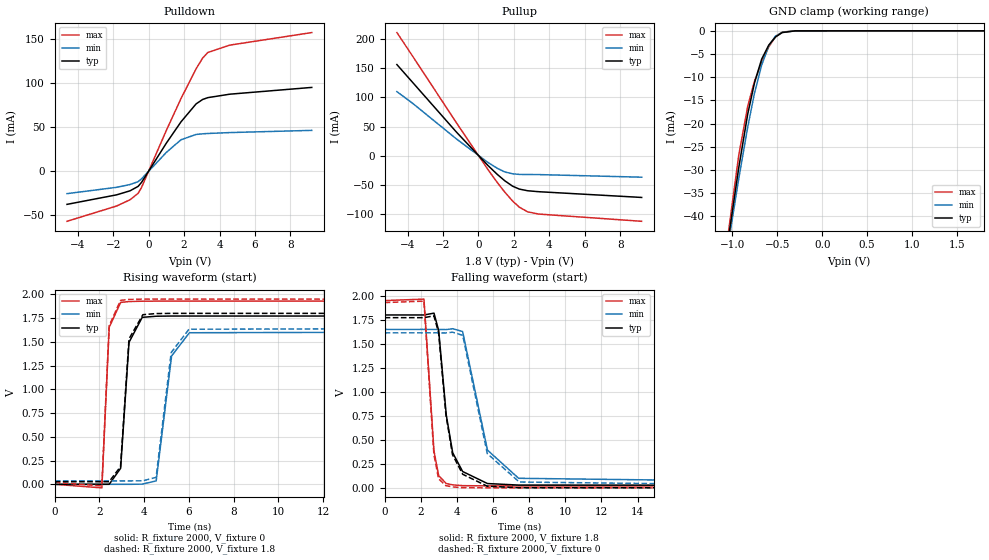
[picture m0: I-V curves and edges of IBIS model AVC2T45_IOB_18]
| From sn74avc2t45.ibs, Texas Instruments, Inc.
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[Model]   AVC2T45_IOB_18
Model_type  I/O
Vinl=0.5775
Vinh=1.2675
Enable   Active-High
Vref =   0
Rref =   2000
Cref =   15p
Vmeas =   0.9
| variable   typ   min   max
C_comp   5.13pF   4.43pF   5.79pF
| C_pullup   4.65pF   3.47pF   6.78pF
| C_pulldown   4.55pF   4.02pF   4.94pF
| C_tri-state   5.13pF   4.43pF   5.79pF
[Temperature Range]   40   100   -40
| Ambient temperature   25   85   -40
[Voltage range]   1.8   1.65   1.95
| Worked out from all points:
|   slope of the pulldown table from 0 to 0.27 V, typ, clamps not added: 30.8 ohm
|   slope of the pullup table from 0 to 0.27 V, typ, clamps not added: 31.4 ohm
|   GND clamp passes 1 mA (typ) near -0.50 V on its own axis
|   rising waveform, R_fixture 2000, V_fixture 0: 20-80 % time 283ps typ, 440ps min, 181ps max; typ from 0 V to 1.77 V
|   falling waveform, R_fixture 2000, V_fixture 1.8: 20-80 % time 647ps typ, 989ps min, 373ps max; typ from 1.8 V to 0.027 V
|   rising waveform, R_fixture 2000, V_fixture 1.8: 20-80 % time 281ps typ, 432ps min, 180ps max; typ from 0.027 V to 1.8 V
|   falling waveform, R_fixture 2000, V_fixture 0: 20-80 % time 649ps typ, 989ps min, 360ps max; typ from 1.77 V to 0 V
[GND Clamp]
| AVC2T45_IOB_18
|   Voltage   I(typ)   I(min)   I(max)
-4.6V     -597.8mA   -546.6mA   -662.5mA
-1.1V     -52.11mA   -52.52mA   -51.59mA
-1.075V   -48.66mA   -49.4mA    -47.7mA
-930mV    -29.5mA    -31.88mA   -26.82mA
-830mV    -17.94mA   -20.74mA   -16.24mA
-755mV    -11.24mA   -13.46mA   -10.89mA
-675mV    -6.119mA   -7.407mA   -6.788mA
-595mV    -3.054mA   -3.247mA   -3.436mA
-520mV    -1.318mA   -1.132mA   -1.268mA
-445mV    -373.4uA   -312uA     -266.4uA
-300mV    -9.535uA   -12.09uA   -2.471uA
1.8V      910.1pA    145.3nA    97.77pA
[Pulldown]
| AVC2T45_IOB_18
|   Voltage   I(typ)   I(min)   I(max)
-4.6V     -37.94mA   -25.73mA   -57.23mA
-1.805V   -27.11mA   -18.54mA   -39.83mA
-1.045V   -22.5mA    -15.36mA   -32.7mA
-590mV    -17.44mA   -12.06mA   -25.35mA
-395mV    -12.81mA   -8.801mA   -18.52mA
1.005V    31.93mA    21.31mA    46.48mA
1.825V    55.97mA    35.61mA    82.46mA
2.68V     76.51mA    41.68mA    116.5mA
3.045V    81.48mA    42.38mA    128.6mA
3.34V     83.6mA     42.77mA    135mA
4.58V     87.53mA    43.81mA    143.4mA
9.2V      95.24mA    46.32mA    157.7mA
[Pullup]
| AVC2T45_IOB_18
|   Voltage   I(typ)   I(min)   I(max)
-4.6V     156.3mA    109.9mA    211.2mA
-3.695V   125.1mA    89.45mA    169.9mA
-1.245V   40.55mA    28.8mA     56.51mA
535mV     -16.77mA   -11.6mA    -23.84mA
1.065V    -32.16mA   -21.66mA   -46.14mA
1.49V     -43.16mA   -27.88mA   -62.67mA
1.925V    -52.28mA   -31.05mA   -77.72mA
2.305V    -57.27mA   -32.09mA   -88.3mA
2.77V     -60.1mA    -32.26mA   -96.25mA
3.4V      -61.74mA   -32.39mA   -100.1mA
9.2V      -71.58mA   -36.85mA   -112.5mA
[Ramp]
| AVC2T45_IOB_18
| variable   typ   min   max
dV/dt_r   1.08/3.00E-10   0.99/4.54E-10   1.18/1.87E-10
dV/dt_f   1.08/6.52E-10   0.98/9.96E-10   1.17/3.77E-10
R_load = 2000
[Rising Waveform]
| AVC2T45_IOB_18
R_fixture =   2000
C_fixture =   0
L_fixture =   0
V_fixture =   0
V_fixture_min = 0
V_fixture_max = 0
|   Time   V(typ)   V(min)   V(max)
0s        21.36nV    98.35nV    643.7pV
2.105ns   38.9uV     6.392nV    -37.29mV
2.435ns   700.4uV    -19.6uV    1.654V
2.945ns   168.9mV    12.07uV    1.915V
3.32ns    1.495V     -166uV     1.925V
3.91ns    1.758V     2.006mV    1.928V
4.535ns   1.77V      36.1mV     1.929V
5.225ns   1.772V     1.352V     1.929V
6.02ns    1.772V     1.596V     1.929V
34.99ns   1.772V     1.614V     1.929V
[Falling Waveform]
| AVC2T45_IOB_18
R_fixture =   2000
C_fixture =   0
L_fixture =   0
V_fixture =   1.8
V_fixture_min = 1.65
V_fixture_max = 1.95
|   Time   V(typ)   V(min)   V(max)
0s        1.8V       1.65V      1.95V
2.175ns   1.8V       1.65V      1.965V
2.73ns    1.819V     1.65V      383.1mV
2.99ns    1.638V     1.649V     127mV
3.41ns    758.3mV    1.648V     44.91mV
3.765ns   365.9mV    1.657V     31.36mV
4.315ns   170.2mV    1.628V     23.04mV
5.69ns    44.91mV    393.1mV    20.55mV
7.415ns   29.02mV    99.5mV     20.46mV
34.99ns   27.15mV    36.2mV     20.45mV
[Rising Waveform]
| AVC2T45_IOB_18
R_fixture =   2000
C_fixture =   0
L_fixture =   0
V_fixture =   1.8
V_fixture_min = 1.65
V_fixture_max = 1.95
|   Time   V(typ)   V(min)   V(max)
0s        27.15mV    36.2mV     20.45mV
2.105ns   27.19mV    36.2mV     -16.69mV
2.43ns    27.76mV    36.19mV    1.669V
2.94ns    186.3mV    36.22mV    1.937V
3.32ns    1.532V     36.04mV    1.947V
3.94ns    1.786V     37.08mV    1.95V
4.53ns    1.798V     73.23mV    1.95V
5.205ns   1.8V       1.387V     1.95V
6ns       1.8V       1.633V     1.95V
34.99ns   1.8V       1.65V      1.95V
[Falling Waveform]
| AVC2T45_IOB_18
R_fixture =   2000
C_fixture =   0
L_fixture =   0
V_fixture =   0
V_fixture_min = 0
V_fixture_max = 0
|   Time   V(typ)   V(min)   V(max)
0s        1.772V     1.614V     1.929V
2.175ns   1.772V     1.614V     1.944V
2.725ns   1.791V     1.615V     347.9mV
2.985ns   1.616V     1.614V     93.85mV
3.39ns    762.5mV    1.613V     23.36mV
3.755ns   345.7mV    1.621V     9.755mV
4.32ns    141.6mV    1.588V     2.155mV
5.68ns    17.04mV    356.6mV    83.83uV
7.45ns    1.541mV    60.71mV    9.3uV
34.99ns   88.35nV    462.3nV    161.6nV
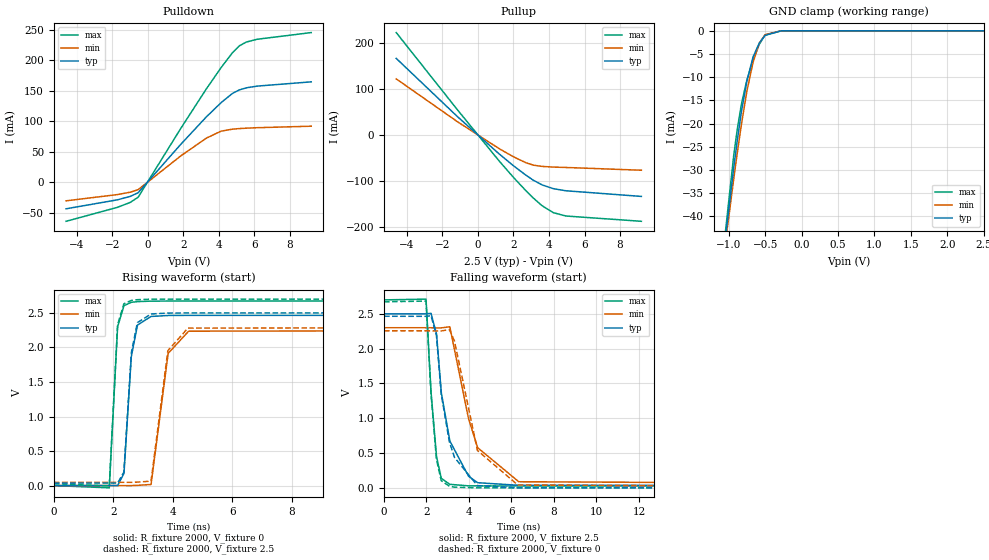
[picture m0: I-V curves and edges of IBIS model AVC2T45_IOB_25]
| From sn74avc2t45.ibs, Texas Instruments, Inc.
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[Model]   AVC2T45_IOB_25
Model_type  I/O
Vinl=0.7
Vinh=1.6
Enable   Active-High
Vref =   0
Rref =   2000
Cref =   15p
Vmeas =   1.25
| variable   typ   min   max
C_comp   4.92pF   4.20pF   5.67pF
| C_pullup   4.12pF   3.15pF   5.54pF
| C_pulldown   4.24pF   3.76pF   4.71pF
| C_tri-state   4.92pF   4.20pF   5.67pF
[Temperature Range]   40   100   -40
| Ambient temperature   25   85   -40
[Voltage range]   2.5   2.3   2.7
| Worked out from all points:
|   slope of the pulldown table from 0 to 0.375 V, typ, clamps not added: 29.4 ohm
|   slope of the pullup table from 0 to 0.375 V, typ, clamps not added: 28.8 ohm
|   GND clamp passes 1 mA (typ) near -0.50 V on its own axis
|   rising waveform, R_fixture 2000, V_fixture 0: 20-80 % time 218ps typ, 341ps min, 154ps max; typ from 0 V to 2.46 V
|   falling waveform, R_fixture 2000, V_fixture 2.5: 20-80 % time 730ps typ, 1.04ns min, 339ps max; typ from 2.5 V to 0.036 V
|   rising waveform, R_fixture 2000, V_fixture 2.5: 20-80 % time 217ps typ, 337ps min, 153ps max; typ from 0.036 V to 2.5 V
|   falling waveform, R_fixture 2000, V_fixture 0: 20-80 % time 722ps typ, 1.04ns min, 331ps max; typ from 2.46 V to 0 V
[GND Clamp]
| AVC2T45_IOB_25
|   Voltage   I(typ)   I(min)   I(max)
-4.6V     -597.8mA   -546.6mA   -662.5mA
-1.105V   -52.8mA    -53.15mA   -52.37mA
-1.08V    -49.35mA   -50.03mA   -48.48mA
-930mV    -29.5mA    -31.88mA   -26.82mA
-880mV    -23.45mA   -26.17mA   -21.02mA
-825mV    -17.44mA   -20.22mA   -15.81mA
-750mV    -10.86mA   -13.03mA   -10.61mA
-665mV    -5.629mA   -6.786mA   -6.326mA
-580mV    -2.642mA   -2.683mA   -2.914mA
-500mV    -988.4uA   -823.5uA   -890.7uA
-280mV    -5.263uA   -7.282uA   -1.131uA
2.5V      1.201nA    548.8nA    148.6pA
[Pulldown]
| AVC2T45_IOB_25
|   Voltage   I(typ)   I(min)   I(max)
-4.6V     -43.76mA   -30.71mA   -64.27mA
-1.71V    -29.04mA   -20.44mA   -41.4mA
-985mV    -23.44mA   -16.53mA   -33.24mA
-545mV    -17.41mA   -12.35mA   -24.86mA
1.85V     61.76mA    42.85mA    87.78mA
3.295V    106.9mA    72.08mA    152.8mA
4.12V     130.1mA    83.49mA    187.5mA
4.755V    145.2mA    86.77mA    211.8mA
5.15V     151.2mA    87.75mA    223.4mA
5.55V     154.6mA    88.43mA    229.7mA
6.155V    157.4mA    89.2mA     234.2mA
9.2V      164.4mA    91.67mA    245.2mA
[Pullup]
| AVC2T45_IOB_25
|   Voltage   I(typ)   I(min)   I(max)
-4.6V     167.2mA    122.6mA    223.3mA
-1.155V   40.55mA    29.45mA    55.44mA
1.195V    -40.71mA   -29.18mA   -56.05mA
2.025V    -67.14mA   -47.36mA   -92.77mA
2.69V     -86.59mA   -59.63mA   -120.2mA
3.115V    -97.78mA   -65.03mA   -136.5mA
3.61V     -108mA     -67.79mA   -153.3mA
4.245V    -116.2mA   -69.29mA   -168.4mA
4.95V     -120.8mA   -70.1mA    -175.7mA
9.2V      -133.1mA   -76.13mA   -187.2mA
[Ramp]
| AVC2T45_IOB_25
| variable   typ   min   max
dV/dt_r   1.49/2.26E-10   1.38/3.53E-10   1.63/1.60E-10
dV/dt_f   1.49/7.30E-10   1.36/1.04E-09   1.61/3.41E-10
R_load = 2000
[Rising Waveform]
| AVC2T45_IOB_25
R_fixture =   2000
C_fixture =   0
L_fixture =   0
V_fixture =   0
V_fixture_min = 0
V_fixture_max = 0
|   Time   V(typ)   V(min)   V(max)
0s        27.74nV    106.5nV    1.06nV
1.865ns   32.51uV    -2.132uV   -33.31mV
2.145ns   165.4uV    -29.52uV   2.299V
2.36ns    176.4mV    35.27uV    2.605V
2.605ns   1.866V     -218.6uV   2.654V
2.815ns   2.325V     3.095mV    2.664V
3.27ns    2.449V     15.8mV     2.671V
3.845ns   2.463V     1.914V     2.672V
4.535ns   2.465V     2.236V     2.672V
34.99ns   2.465V     2.256V     2.672V
[Falling Waveform]
| AVC2T45_IOB_25
R_fixture =   2000
C_fixture =   0
L_fixture =   0
V_fixture =   2.5
V_fixture_min = 2.3
V_fixture_max = 2.7
|   Time   V(typ)   V(min)   V(max)
0s        2.5V       2.3V       2.7V
1.98ns    2.499V     2.3V       2.711V
2.215ns   2.507V     2.3V       1.379V
2.475ns   2.208V     2.298V     446.3mV
2.7ns     1.365V     2.298V     136.1mV
3.1ns     673.8mV    2.314V     50.62mV
3.98ns    166.9mV    994.7mV    29.02mV
4.41ns    73.94mV    576.5mV    28.03mV
6.345ns   36.64mV    87.91mV    27.63mV
34.99ns   36.05mV    46.86mV    27.62mV
[Rising Waveform]
| AVC2T45_IOB_25
R_fixture =   2000
C_fixture =   0
L_fixture =   0
V_fixture =   2.5
V_fixture_min = 2.3
V_fixture_max = 2.7
|   Time   V(typ)   V(min)   V(max)
0s        36.05mV    46.86mV    27.62mV
1.865ns   36.09mV    46.85mV    -5.701mV
2.145ns   36.2mV     46.83mV    2.331V
2.355ns   193.7mV    46.89mV    2.632V
2.61ns    1.933V     46.65mV    2.682V
2.81ns    2.36V      49.84mV    2.692V
3.27ns    2.485V     64.05mV    2.699V
3.835ns   2.498V     1.954V     2.7V
4.51ns    2.5V       2.28V      2.7V
34.99ns   2.5V       2.3V       2.7V
[Falling Waveform]
| AVC2T45_IOB_25
R_fixture =   2000
C_fixture =   0
L_fixture =   0
V_fixture =   0
V_fixture_min = 0
V_fixture_max = 0
|   Time   V(typ)   V(min)   V(max)
0s        2.465V     2.256V     2.672V
1.98ns    2.464V     2.256V     2.683V
2.215ns   2.472V     2.256V     1.351V
2.47ns    2.189V     2.254V     407mV
2.695ns   1.347V     2.254V     103.7mV
3.08ns    659.5mV    2.273V     22.93mV
3.32ns    437mV      2.107V     10.44mV
4.4ns     31.98mV    537mV      385.4uV
6.3ns     508.2uV    40.75mV    13.68uV
34.99ns   384.9nV    342nV      234.7nV
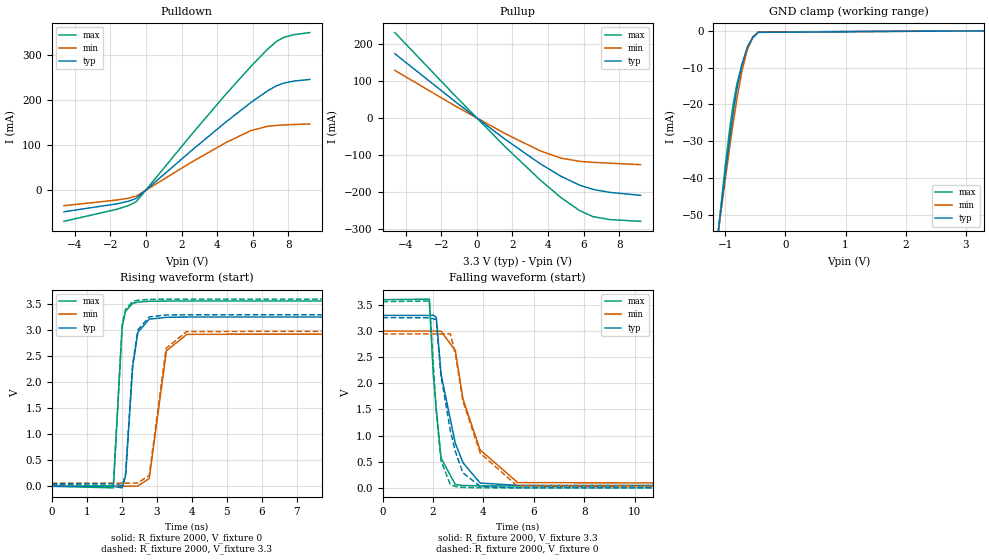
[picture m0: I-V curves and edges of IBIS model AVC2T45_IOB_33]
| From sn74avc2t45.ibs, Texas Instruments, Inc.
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[Model]   AVC2T45_IOB_33
Model_type  I/O
Vinl=0.8
Vinh=2.0
Enable   Active-High
Vref =   0
Rref =   2000
Cref =   15p
Vmeas =   1.65
| variable   typ   min   max
C_comp   4.80pF   3.94pF   5.78pF
| C_pullup   3.85pF   2.95pF   5.15pF
| C_pulldown   4.06pF   3.58pF   4.64pF
| C_tri-state   4.80pF   3.94pF   5.78pF
[Temperature Range]   40   100   -40
| Ambient temperature   25   85   -40
[Voltage range]   3.3   3   3.6
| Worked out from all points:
|   slope of the pulldown table from 0 to 0.495 V, typ, clamps not added: 28.7 ohm
|   slope of the pullup table from 0 to 0.495 V, typ, clamps not added: 27.4 ohm
|   GND clamp passes 1 mA (typ) near -0.50 V on its own axis
|   rising waveform, R_fixture 2000, V_fixture 0: 20-80 % time 197ps typ, 301ps min, 140ps max; typ from 0 V to 3.26 V
|   falling waveform, R_fixture 2000, V_fixture 3.3: 20-80 % time 746ps typ, 1ns min, 327ps max; typ from 3.3 V to 0.046 V
|   rising waveform, R_fixture 2000, V_fixture 3.3: 20-80 % time 196ps typ, 297ps min, 139ps max; typ from 0.046 V to 3.3 V
|   falling waveform, R_fixture 2000, V_fixture 0: 20-80 % time 663ps typ, 1ns min, 323ps max; typ from 3.26 V to 0 V
[GND Clamp]
| AVC2T45_IOB_33
|   Voltage   I(typ)   I(min)   I(max)
-4.6V     -597.8mA   -546.6mA   -662.5mA
-1.12V    -54.88mA   -55.04mA   -54.73mA
-1.09V    -50.72mA   -51.27mA   -50.03mA
-1V       -38.53mA   -40.19mA   -36.43mA
-920mV    -28.25mA   -30.71mA   -25.57mA
-870mV    -22.29mA   -25.06mA   -19.99mA
-810mV    -15.96mA   -18.69mA   -14.59mA
-725mV    -9.083mA   -10.96mA   -9.257mA
-630mV    -4.179mA   -4.838mA   -4.797mA
-545mV    -1.809mA   -1.649mA   -1.862mA
-450mV    -412.7uA   -343uA     -301.7uA
3.3V      1.631nA    2.406uA    228.2pA
[Pulldown]
| AVC2T45_IOB_33
|   Voltage   I(typ)   I(min)   I(max)
-4.6V     -47.48mA   -33.99mA   -68.59mA
-1.68V    -30.25mA   -21.7mA    -42.42mA
-975mV    -24.15mA   -17.32mA   -33.81mA
-545mV    -17.86mA   -12.84mA   -25.24mA
2.54V     87.35mA    61.85mA    122.6mA
4.5V      151.6mA    105.9mA    213.3mA
5.905V    194.7mA    132.4mA    274.8mA
6.805V    219.6mA    141.6mA    311.5mA
7.315V    231.2mA    143.7mA    329.3mA
7.73V     237.3mA    144.7mA    338.5mA
8.275V    241.7mA    145.7mA    344.4mA
9.2V      245.6mA    146.9mA    349.3mA
[Pullup]
| AVC2T45_IOB_33
|   Voltage   I(typ)   I(min)   I(max)
-4.6V     174.2mA    129.1mA    231.4mA
-1.105V   40.58mA    29.86mA    54.82mA
1.58V     -56.83mA   -41.58mA   -76.89mA
3.53V     -122.6mA   -88.07mA   -166.1mA
4.725V    -157.4mA   -108.5mA   -215.1mA
5.775V    -181.6mA   -117mA     -250.3mA
6.525V    -192.9mA   -119.7mA   -266.7mA
7.46V     -201mA     -122mA     -274.6mA
9.2V      -209mA     -126mA     -279.3mA
[Ramp]
| AVC2T45_IOB_33
| variable   typ   min   max
dV/dt_r   1.98/2.02E-10   1.79/3.12E-10   2.16/1.42E-10
dV/dt_f   1.97/7.47E-10   1.78/1.00E-09   2.15/3.27E-10
R_load = 2000
[Rising Waveform]
| AVC2T45_IOB_33
R_fixture =   2000
C_fixture =   0
L_fixture =   0
V_fixture =   0
V_fixture_min = 0
V_fixture_max = 0
|   Time   V(typ)   V(min)   V(max)
0s        38nV       120.5nV    1.922nV
1.76ns    -33.8uV    -5.639uV   -30.94mV
2.01ns    -30.65mV   28.08uV    3.059V
2.11ns    195.6mV    25.47uV    3.369V
2.31ns    2.289V     323.3uV    3.518V
2.46ns    2.96V      4.611mV    3.543V
2.785ns   3.214V     149.7mV    3.559V
3.275ns   3.25V      2.606V     3.563V
3.86ns    3.255V     2.923V     3.564V
34.99ns   3.256V     2.946V     3.564V
[Falling Waveform]
| AVC2T45_IOB_33
R_fixture =   2000
C_fixture =   0
L_fixture =   0
V_fixture =   3.3
V_fixture_min = 3
V_fixture_max = 3.6
|   Time   V(typ)   V(min)   V(max)
0s        3.3V       3V         3.6V
1.855ns   3.298V     3V         3.611V
2.015ns   3.307V     3V         2.141V
2.13ns    3.262V     2.999V     1.508V
2.32ns    2.175V     2.996V     570.9mV
2.885ns   854.9mV    2.63V      64.3mV
3.19ns    480.7mV    1.698V     45.52mV
3.87ns    91.53mV    725.2mV    37.29mV
5.36ns    47.4mV     101.4mV    36.36mV
34.99ns   46.48mV    58.85mV    36.33mV
[Rising Waveform]
| AVC2T45_IOB_33
R_fixture =   2000
C_fixture =   0
L_fixture =   0
V_fixture =   3.3
V_fixture_min = 3
V_fixture_max = 3.6
|   Time   V(typ)   V(min)   V(max)
0s        46.48mV    58.85mV    36.33mV
1.76ns    46.44mV    58.84mV    5.278mV
2.015ns   14.21mV    58.88mV    3.125V
2.11ns    243.1mV    58.88mV    3.406V
2.31ns    2.341V     59.18mV    3.554V
2.46ns    3.008V     63.48mV    3.579V
2.785ns   3.259V     210.8mV    3.595V
3.265ns   3.294V     2.651V     3.599V
3.85ns    3.299V     2.977V     3.6V
34.99ns   3.3V       3V         3.6V
[Falling Waveform]
| AVC2T45_IOB_33
R_fixture =   2000
C_fixture =   0
L_fixture =   0
V_fixture =   0
V_fixture_min = 0
V_fixture_max = 0
|   Time   V(typ)   V(min)   V(max)
0s        3.256V     2.946V     3.564V
1.855ns   3.254V     2.946V     3.575V
2.13ns    3.218V     2.945V     1.467V
2.32ns    2.136V     2.942V     518.5mV
2.69ns    1.093V     2.948V     59.64mV
2.895ns   683.2mV    2.543V     26.14mV
3.185ns   288.5mV    1.663V     9.038mV
3.875ns   26.55mV    662.4mV    916.2uV
5.33ns    578.4uV    42.4mV     32.69uV
34.99ns   493.4nV    724nV      209.7nV
